VERSION 5.7 ;
BUSBITCHARS "[]" ;
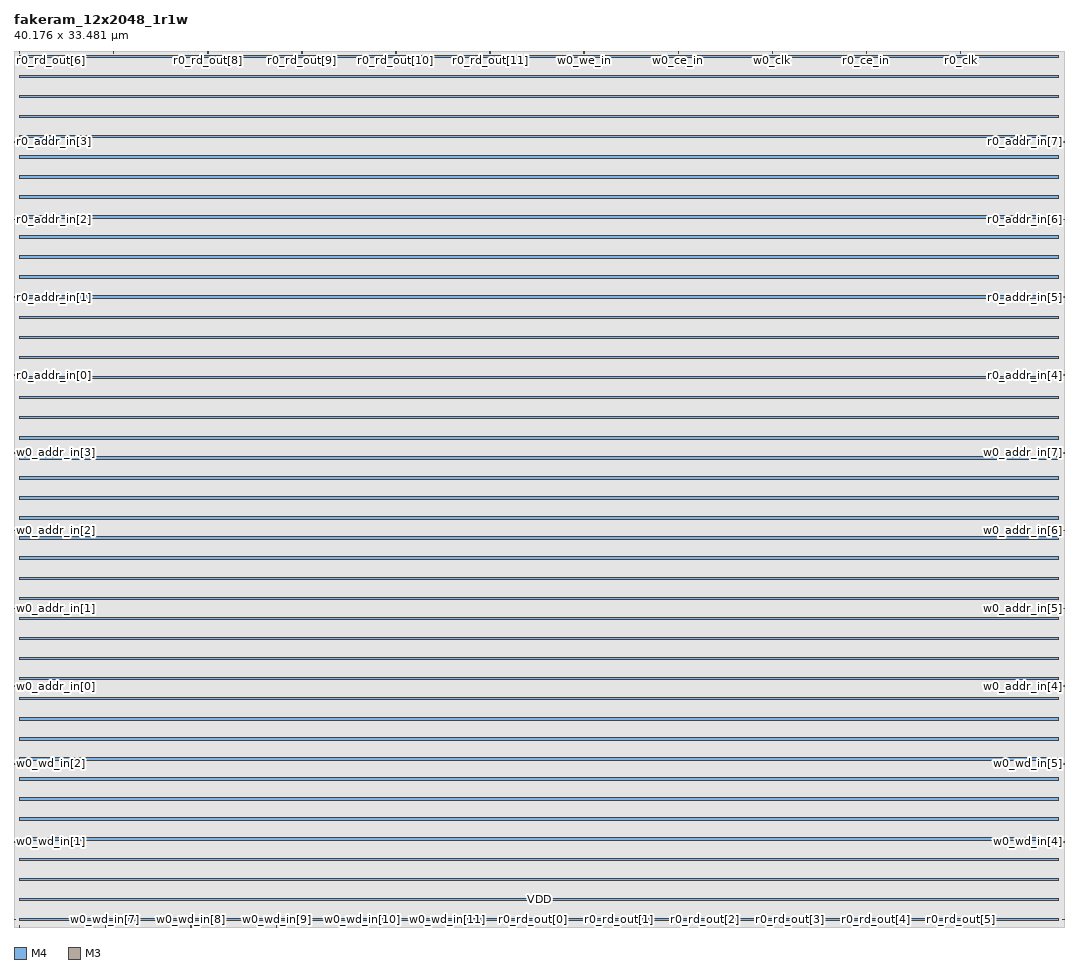
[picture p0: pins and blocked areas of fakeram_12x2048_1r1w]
MACRO fakeram_12x2048_1r1w
  FOREIGN fakeram_12x2048_1r1w 0 0 ;
  SYMMETRY X Y R90 ;
  SIZE 40.176 BY 33.481 ;
  CLASS BLOCK ;
  PIN w0_wd_in[0]
    DIRECTION INPUT ;
    USE SIGNAL ;
    SHAPE ABUTMENT ;
    PORT
      LAYER M4 ;
      RECT 0.000 0.276 0.072 0.300 ;
    END
  END w0_wd_in[0]
  PIN w0_wd_in[1]
    DIRECTION INPUT ;
    USE SIGNAL ;
    SHAPE ABUTMENT ;
    PORT
      LAYER M4 ;
      RECT 0.000 3.252 0.072 3.276 ;
    END
  END w0_wd_in[1]
  PIN w0_wd_in[2]
    DIRECTION INPUT ;
    USE SIGNAL ;
    SHAPE ABUTMENT ;
    PORT
      LAYER M4 ;
      RECT 0.000 6.228 0.072 6.252 ;
    END
  END w0_wd_in[2]
  PIN w0_wd_in[3]
    DIRECTION INPUT ;
    USE SIGNAL ;
    SHAPE ABUTMENT ;
    PORT
      LAYER M4 ;
      RECT 40.104 0.276 40.176 0.300 ;
    END
  END w0_wd_in[3]
  PIN w0_wd_in[4]
    DIRECTION INPUT ;
    USE SIGNAL ;
    SHAPE ABUTMENT ;
    PORT
      LAYER M4 ;
      RECT 40.104 3.252 40.176 3.276 ;
    END
  END w0_wd_in[4]
  PIN w0_wd_in[5]
    DIRECTION INPUT ;
    USE SIGNAL ;
    SHAPE ABUTMENT ;
    PORT
      LAYER M4 ;
      RECT 40.104 6.228 40.176 6.252 ;
    END
  END w0_wd_in[5]
  PIN w0_wd_in[6]
    DIRECTION INPUT ;
    USE SIGNAL ;
    SHAPE ABUTMENT ;
    PORT
      LAYER M3 ;
      RECT 0.207 0.000 0.225 0.054 ;
    END
  END w0_wd_in[6]
  PIN w0_wd_in[7]
    DIRECTION INPUT ;
    USE SIGNAL ;
    SHAPE ABUTMENT ;
    PORT
      LAYER M3 ;
      RECT 3.483 0.000 3.501 0.054 ;
    END
  END w0_wd_in[7]
  PIN w0_wd_in[8]
    DIRECTION INPUT ;
    USE SIGNAL ;
    SHAPE ABUTMENT ;
    PORT
      LAYER M3 ;
      RECT 6.759 0.000 6.777 0.054 ;
    END
  END w0_wd_in[8]
  PIN w0_wd_in[9]
    DIRECTION INPUT ;
    USE SIGNAL ;
    SHAPE ABUTMENT ;
    PORT
      LAYER M3 ;
      RECT 10.035 0.000 10.053 0.054 ;
    END
  END w0_wd_in[9]
  PIN w0_wd_in[10]
    DIRECTION INPUT ;
    USE SIGNAL ;
    SHAPE ABUTMENT ;
    PORT
      LAYER M3 ;
      RECT 13.311 0.000 13.329 0.054 ;
    END
  END w0_wd_in[10]
  PIN w0_wd_in[11]
    DIRECTION INPUT ;
    USE SIGNAL ;
    SHAPE ABUTMENT ;
    PORT
      LAYER M3 ;
      RECT 16.587 0.000 16.605 0.054 ;
    END
  END w0_wd_in[11]
  PIN r0_rd_out[0]
    DIRECTION OUTPUT ;
    USE SIGNAL ;
    SHAPE ABUTMENT ;
    PORT
      LAYER M3 ;
      RECT 19.863 0.000 19.881 0.054 ;
    END
  END r0_rd_out[0]
  PIN r0_rd_out[1]
    DIRECTION OUTPUT ;
    USE SIGNAL ;
    SHAPE ABUTMENT ;
    PORT
      LAYER M3 ;
      RECT 23.139 0.000 23.157 0.054 ;
    END
  END r0_rd_out[1]
  PIN r0_rd_out[2]
    DIRECTION OUTPUT ;
    USE SIGNAL ;
    SHAPE ABUTMENT ;
    PORT
      LAYER M3 ;
      RECT 26.415 0.000 26.433 0.054 ;
    END
  END r0_rd_out[2]
  PIN r0_rd_out[3]
    DIRECTION OUTPUT ;
    USE SIGNAL ;
    SHAPE ABUTMENT ;
    PORT
      LAYER M3 ;
      RECT 29.691 0.000 29.709 0.054 ;
    END
  END r0_rd_out[3]
  PIN r0_rd_out[4]
    DIRECTION OUTPUT ;
    USE SIGNAL ;
    SHAPE ABUTMENT ;
    PORT
      LAYER M3 ;
      RECT 32.967 0.000 32.985 0.054 ;
    END
  END r0_rd_out[4]
  PIN r0_rd_out[5]
    DIRECTION OUTPUT ;
    USE SIGNAL ;
    SHAPE ABUTMENT ;
    PORT
      LAYER M3 ;
      RECT 36.243 0.000 36.261 0.054 ;
    END
  END r0_rd_out[5]
  PIN r0_rd_out[6]
    DIRECTION OUTPUT ;
    USE SIGNAL ;
    SHAPE ABUTMENT ;
    PORT
      LAYER M3 ;
      RECT 0.207 33.427 0.225 33.481 ;
    END
  END r0_rd_out[6]
  PIN r0_rd_out[7]
    DIRECTION OUTPUT ;
    USE SIGNAL ;
    SHAPE ABUTMENT ;
    PORT
      LAYER M3 ;
      RECT 3.807 33.427 3.825 33.481 ;
    END
  END r0_rd_out[7]
  PIN r0_rd_out[8]
    DIRECTION OUTPUT ;
    USE SIGNAL ;
    SHAPE ABUTMENT ;
    PORT
      LAYER M3 ;
      RECT 7.407 33.427 7.425 33.481 ;
    END
  END r0_rd_out[8]
  PIN r0_rd_out[9]
    DIRECTION OUTPUT ;
    USE SIGNAL ;
    SHAPE ABUTMENT ;
    PORT
      LAYER M3 ;
      RECT 11.007 33.427 11.025 33.481 ;
    END
  END r0_rd_out[9]
  PIN r0_rd_out[10]
    DIRECTION OUTPUT ;
    USE SIGNAL ;
    SHAPE ABUTMENT ;
    PORT
      LAYER M3 ;
      RECT 14.607 33.427 14.625 33.481 ;
    END
  END r0_rd_out[10]
  PIN r0_rd_out[11]
    DIRECTION OUTPUT ;
    USE SIGNAL ;
    SHAPE ABUTMENT ;
    PORT
      LAYER M3 ;
      RECT 18.207 33.427 18.225 33.481 ;
    END
  END r0_rd_out[11]
  PIN w0_addr_in[0]
    DIRECTION INPUT ;
    USE SIGNAL ;
    SHAPE ABUTMENT ;
    PORT
      LAYER M4 ;
      RECT 0.000 9.204 0.072 9.228 ;
    END
  END w0_addr_in[0]
  PIN w0_addr_in[1]
    DIRECTION INPUT ;
    USE SIGNAL ;
    SHAPE ABUTMENT ;
    PORT
      LAYER M4 ;
      RECT 0.000 12.180 0.072 12.204 ;
    END
  END w0_addr_in[1]
  PIN w0_addr_in[2]
    DIRECTION INPUT ;
    USE SIGNAL ;
    SHAPE ABUTMENT ;
    PORT
      LAYER M4 ;
      RECT 0.000 15.156 0.072 15.180 ;
    END
  END w0_addr_in[2]
  PIN w0_addr_in[3]
    DIRECTION INPUT ;
    USE SIGNAL ;
    SHAPE ABUTMENT ;
    PORT
      LAYER M4 ;
      RECT 0.000 18.132 0.072 18.156 ;
    END
  END w0_addr_in[3]
  PIN w0_addr_in[4]
    DIRECTION INPUT ;
    USE SIGNAL ;
    SHAPE ABUTMENT ;
    PORT
      LAYER M4 ;
      RECT 40.104 9.204 40.176 9.228 ;
    END
  END w0_addr_in[4]
  PIN w0_addr_in[5]
    DIRECTION INPUT ;
    USE SIGNAL ;
    SHAPE ABUTMENT ;
    PORT
      LAYER M4 ;
      RECT 40.104 12.180 40.176 12.204 ;
    END
  END w0_addr_in[5]
  PIN w0_addr_in[6]
    DIRECTION INPUT ;
    USE SIGNAL ;
    SHAPE ABUTMENT ;
    PORT
      LAYER M4 ;
      RECT 40.104 15.156 40.176 15.180 ;
    END
  END w0_addr_in[6]
  PIN w0_addr_in[7]
    DIRECTION INPUT ;
    USE SIGNAL ;
    SHAPE ABUTMENT ;
    PORT
      LAYER M4 ;
      RECT 40.104 18.132 40.176 18.156 ;
    END
  END w0_addr_in[7]
  PIN r0_addr_in[0]
    DIRECTION INPUT ;
    USE SIGNAL ;
    SHAPE ABUTMENT ;
    PORT
      LAYER M4 ;
      RECT 0.000 21.108 0.072 21.132 ;
    END
  END r0_addr_in[0]
  PIN r0_addr_in[1]
    DIRECTION INPUT ;
    USE SIGNAL ;
    SHAPE ABUTMENT ;
    PORT
      LAYER M4 ;
      RECT 0.000 24.084 0.072 24.108 ;
    END
  END r0_addr_in[1]
  PIN r0_addr_in[2]
    DIRECTION INPUT ;
    USE SIGNAL ;
    SHAPE ABUTMENT ;
    PORT
      LAYER M4 ;
      RECT 0.000 27.060 0.072 27.084 ;
    END
  END r0_addr_in[2]
  PIN r0_addr_in[3]
    DIRECTION INPUT ;
    USE SIGNAL ;
    SHAPE ABUTMENT ;
    PORT
      LAYER M4 ;
      RECT 0.000 30.036 0.072 30.060 ;
    END
  END r0_addr_in[3]
  PIN r0_addr_in[4]
    DIRECTION INPUT ;
    USE SIGNAL ;
    SHAPE ABUTMENT ;
    PORT
      LAYER M4 ;
      RECT 40.104 21.108 40.176 21.132 ;
    END
  END r0_addr_in[4]
  PIN r0_addr_in[5]
    DIRECTION INPUT ;
    USE SIGNAL ;
    SHAPE ABUTMENT ;
    PORT
      LAYER M4 ;
      RECT 40.104 24.084 40.176 24.108 ;
    END
  END r0_addr_in[5]
  PIN r0_addr_in[6]
    DIRECTION INPUT ;
    USE SIGNAL ;
    SHAPE ABUTMENT ;
    PORT
      LAYER M4 ;
      RECT 40.104 27.060 40.176 27.084 ;
    END
  END r0_addr_in[6]
  PIN r0_addr_in[7]
    DIRECTION INPUT ;
    USE SIGNAL ;
    SHAPE ABUTMENT ;
    PORT
      LAYER M4 ;
      RECT 40.104 30.036 40.176 30.060 ;
    END
  END r0_addr_in[7]
  PIN w0_we_in
    DIRECTION INPUT ;
    USE SIGNAL ;
    SHAPE ABUTMENT ;
    PORT
      LAYER M3 ;
      RECT 21.807 33.427 21.825 33.481 ;
    END
  END w0_we_in
  PIN w0_ce_in
    DIRECTION INPUT ;
    USE SIGNAL ;
    SHAPE ABUTMENT ;
    PORT
      LAYER M3 ;
      RECT 25.407 33.427 25.425 33.481 ;
    END
  END w0_ce_in
  PIN w0_clk
    DIRECTION INPUT ;
    USE SIGNAL ;
    SHAPE ABUTMENT ;
    PORT
      LAYER M3 ;
      RECT 29.007 33.427 29.025 33.481 ;
    END
  END w0_clk
  PIN r0_ce_in
    DIRECTION INPUT ;
    USE SIGNAL ;
    SHAPE ABUTMENT ;
    PORT
      LAYER M3 ;
      RECT 32.607 33.427 32.625 33.481 ;
    END
  END r0_ce_in
  PIN r0_clk
    DIRECTION INPUT ;
    USE SIGNAL ;
    SHAPE ABUTMENT ;
    PORT
      LAYER M3 ;
      RECT 36.207 33.427 36.225 33.481 ;
    END
  END r0_clk
  PIN VSS
    DIRECTION INOUT ;
    USE GROUND ;
    PORT
      LAYER M4 ;
      RECT 0.216 0.240 39.960 0.336 ;
      RECT 0.216 1.008 39.960 1.104 ;
      RECT 0.216 1.776 39.960 1.872 ;
      RECT 0.216 2.544 39.960 2.640 ;
      RECT 0.216 3.312 39.960 3.408 ;
      RECT 0.216 4.080 39.960 4.176 ;
      RECT 0.216 4.848 39.960 4.944 ;
      RECT 0.216 5.616 39.960 5.712 ;
      RECT 0.216 6.384 39.960 6.480 ;
      RECT 0.216 7.152 39.960 7.248 ;
      RECT 0.216 7.920 39.960 8.016 ;
      RECT 0.216 8.688 39.960 8.784 ;
      RECT 0.216 9.456 39.960 9.552 ;
      RECT 0.216 10.224 39.960 10.320 ;
      RECT 0.216 10.992 39.960 11.088 ;
      RECT 0.216 11.760 39.960 11.856 ;
      RECT 0.216 12.528 39.960 12.624 ;
      RECT 0.216 13.296 39.960 13.392 ;
      RECT 0.216 14.064 39.960 14.160 ;
      RECT 0.216 14.832 39.960 14.928 ;
      RECT 0.216 15.600 39.960 15.696 ;
      RECT 0.216 16.368 39.960 16.464 ;
      RECT 0.216 17.136 39.960 17.232 ;
      RECT 0.216 17.904 39.960 18.000 ;
      RECT 0.216 18.672 39.960 18.768 ;
      RECT 0.216 19.440 39.960 19.536 ;
      RECT 0.216 20.208 39.960 20.304 ;
      RECT 0.216 20.976 39.960 21.072 ;
      RECT 0.216 21.744 39.960 21.840 ;
      RECT 0.216 22.512 39.960 22.608 ;
      RECT 0.216 23.280 39.960 23.376 ;
      RECT 0.216 24.048 39.960 24.144 ;
      RECT 0.216 24.816 39.960 24.912 ;
      RECT 0.216 25.584 39.960 25.680 ;
      RECT 0.216 26.352 39.960 26.448 ;
      RECT 0.216 27.120 39.960 27.216 ;
      RECT 0.216 27.888 39.960 27.984 ;
      RECT 0.216 28.656 39.960 28.752 ;
      RECT 0.216 29.424 39.960 29.520 ;
      RECT 0.216 30.192 39.960 30.288 ;
      RECT 0.216 30.960 39.960 31.056 ;
      RECT 0.216 31.728 39.960 31.824 ;
      RECT 0.216 32.496 39.960 32.592 ;
      RECT 0.216 33.264 39.960 33.360 ;
    END
  END VSS
  PIN VDD
    DIRECTION INOUT ;
    USE POWER ;
    PORT
      LAYER M4 ;
      RECT 0.216 0.240 39.960 0.336 ;
      RECT 0.216 1.008 39.960 1.104 ;
      RECT 0.216 1.776 39.960 1.872 ;
      RECT 0.216 2.544 39.960 2.640 ;
      RECT 0.216 3.312 39.960 3.408 ;
      RECT 0.216 4.080 39.960 4.176 ;
      RECT 0.216 4.848 39.960 4.944 ;
      RECT 0.216 5.616 39.960 5.712 ;
      RECT 0.216 6.384 39.960 6.480 ;
      RECT 0.216 7.152 39.960 7.248 ;
      RECT 0.216 7.920 39.960 8.016 ;
      RECT 0.216 8.688 39.960 8.784 ;
      RECT 0.216 9.456 39.960 9.552 ;
      RECT 0.216 10.224 39.960 10.320 ;
      RECT 0.216 10.992 39.960 11.088 ;
      RECT 0.216 11.760 39.960 11.856 ;
      RECT 0.216 12.528 39.960 12.624 ;
      RECT 0.216 13.296 39.960 13.392 ;
      RECT 0.216 14.064 39.960 14.160 ;
      RECT 0.216 14.832 39.960 14.928 ;
      RECT 0.216 15.600 39.960 15.696 ;
      RECT 0.216 16.368 39.960 16.464 ;
      RECT 0.216 17.136 39.960 17.232 ;
      RECT 0.216 17.904 39.960 18.000 ;
      RECT 0.216 18.672 39.960 18.768 ;
      RECT 0.216 19.440 39.960 19.536 ;
      RECT 0.216 20.208 39.960 20.304 ;
      RECT 0.216 20.976 39.960 21.072 ;
      RECT 0.216 21.744 39.960 21.840 ;
      RECT 0.216 22.512 39.960 22.608 ;
      RECT 0.216 23.280 39.960 23.376 ;
      RECT 0.216 24.048 39.960 24.144 ;
      RECT 0.216 24.816 39.960 24.912 ;
      RECT 0.216 25.584 39.960 25.680 ;
      RECT 0.216 26.352 39.960 26.448 ;
      RECT 0.216 27.120 39.960 27.216 ;
      RECT 0.216 27.888 39.960 27.984 ;
      RECT 0.216 28.656 39.960 28.752 ;
      RECT 0.216 29.424 39.960 29.520 ;
      RECT 0.216 30.192 39.960 30.288 ;
      RECT 0.216 30.960 39.960 31.056 ;
      RECT 0.216 31.728 39.960 31.824 ;
      RECT 0.216 32.496 39.960 32.592 ;
      RECT 0.216 33.264 39.960 33.360 ;
    END
  END VDD
  OBS
    LAYER M1 ;
    RECT 0 0 40.176 33.481 ;
    LAYER M2 ;
    RECT 0 0 40.176 33.481 ;
    LAYER M3 ;
    RECT 0 0 40.176 33.481 ;
    LAYER M4 ;
    RECT 0 0 40.176 33.481 ;
  END
END fakeram_12x2048_1r1w

END LIBRARY
